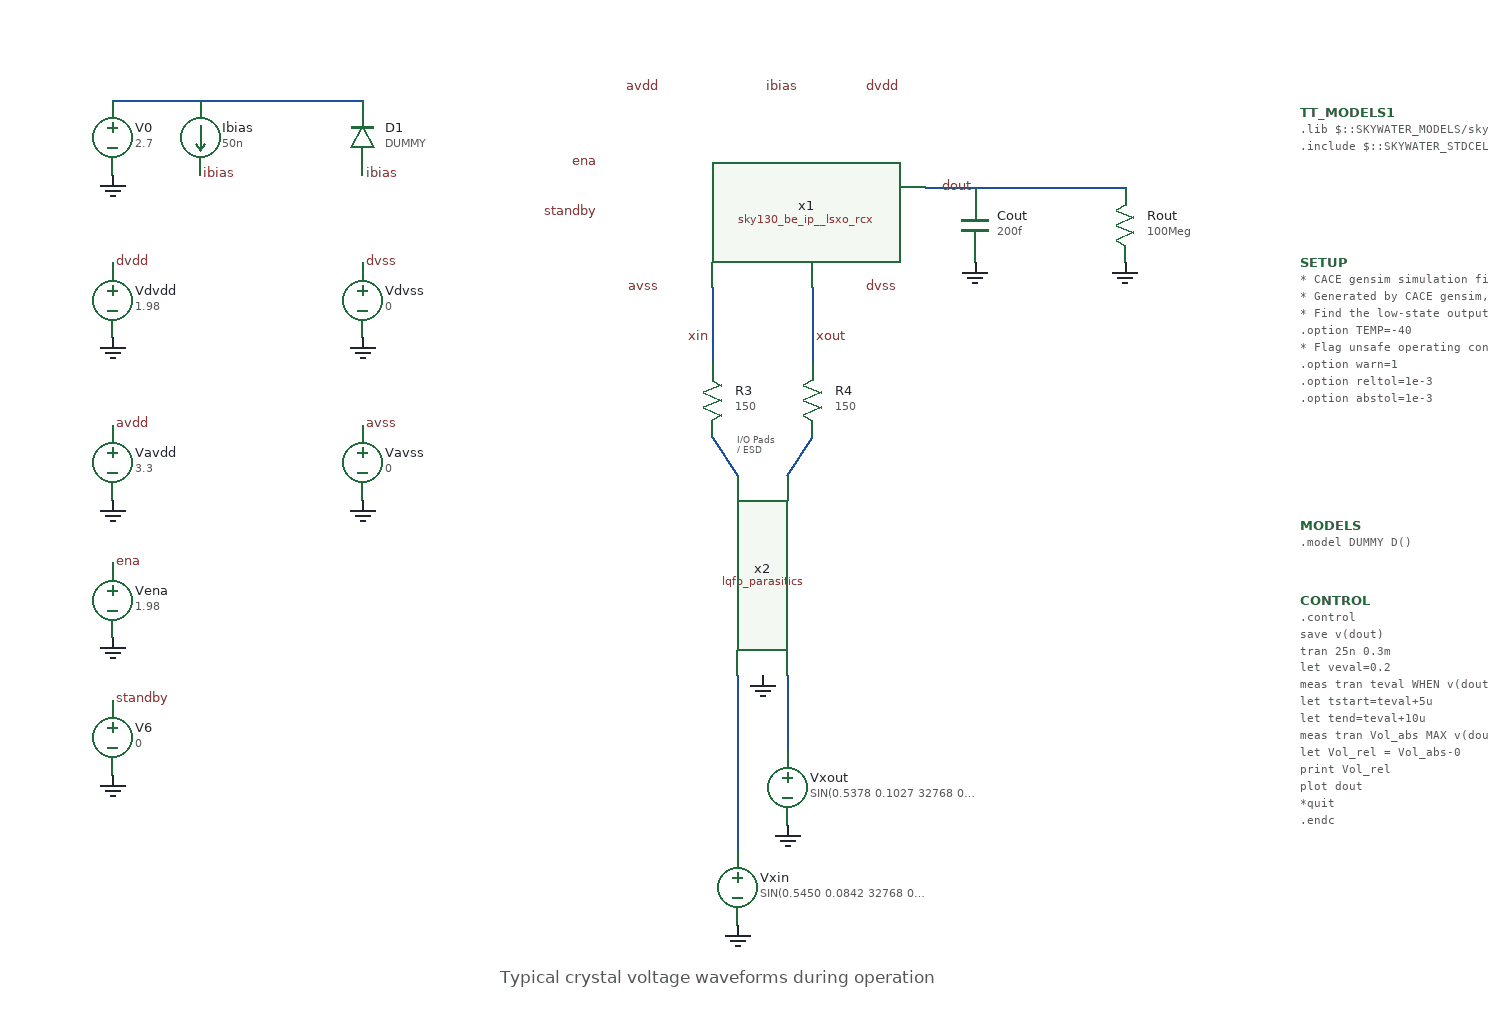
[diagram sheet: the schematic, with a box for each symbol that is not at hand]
v {xschem version=3.4.5 file_version=1.2
}
G {}
K {}
V {}
S {}
E {}
T {I/O Pads 
/ ESD} 540 -460 0 0 0.2 0.2 {}
T {Typical crystal voltage waveforms during operation} 350 -30 0 0 0.4 0.4 {}
N 40 -720 110 -720 {
lab=#net1}
N 600 -570 600 -510 {
lab=xout}
N 520 -570 520 -510 {
lab=xin}
N 520 -450 540 -420 {
lab=#net2}
N 580 -420 600 -450 {
lab=#net3}
N 110 -720 240 -720 {
lab=#net1}
N 690 -650 730 -650 {
lab=dout}
N 730 -650 850 -650 {
lab=dout}
N 540 -260 540 -120 {
lab=#net4}
N 580 -260 580 -200 {
lab=#net5}
C {devices/vsource.sym} 40 -560 0 0 {name=Vdvdd value=1.98 savecurrent=false}
C {devices/vsource.sym} 40 -430 0 0 {name=Vavdd value=3.3 savecurrent=false}
C {devices/lab_pin.sym} 40 -460 2 0 {name=p1 sig_type=std_logic lab=avdd}
C {devices/lab_pin.sym} 40 -590 2 0 {name=p2 sig_type=std_logic lab=dvdd}
C {devices/lab_pin.sym} 430 -670 0 0 {name=p3 sig_type=std_logic lab=ena
}
C {devices/code_shown.sym} 990 -380 0 0 {name=MODELS 
only_toplevel=true
value=".model DUMMY D()"}
C {devices/isource.sym} 110 -690 0 0 {name=Ibias value=50n}
C {devices/capa.sym} 730 -620 0 0 {name=Cout
m=1
value=200f
footprint=1206
device="ceramic capacitor"}
C {devices/gnd.sym} 730 -590 0 0 {name=l9 lab=GND}
C {devices/lab_pin.sym} 730 -650 1 0 {name=p16 sig_type=std_logic lab=dout}
C {devices/lab_pin.sym} 110 -660 2 0 {name=p17 sig_type=std_logic lab=ibias}
C {devices/vsource.sym} 40 -690 0 0 {name=V0 value=2.7 savecurrent=false}
C {devices/gnd.sym} 40 -660 0 0 {name=l10 lab=GND}
C {devices/lab_pin.sym} 520 -530 0 0 {name=p15 sig_type=std_logic lab=xin}
C {devices/lab_pin.sym} 600 -530 2 0 {name=p18 sig_type=std_logic lab=xout}
C {devices/lab_pin.sym} 480 -730 0 0 {name=p20 sig_type=std_logic lab=avdd}
C {devices/lab_pin.sym} 640 -730 2 0 {name=p22 sig_type=std_logic lab=dvdd}
C {devices/gnd.sym} 40 -530 0 0 {name=l1 lab=GND}
C {devices/gnd.sym} 40 -400 0 0 {name=l2 lab=GND}
C {devices/lab_pin.sym} 560 -730 2 0 {name=p11 sig_type=std_logic lab=ibias}
C {devices/gnd.sym} 40 -290 0 0 {name=l11 lab=GND}
C {devices/lab_pin.sym} 40 -350 2 0 {name=p4 sig_type=std_logic lab=ena}
C {devices/vsource.sym} 40 -210 0 0 {name=V6 value=0 savecurrent=false}
C {devices/gnd.sym} 40 -180 0 0 {name=l12 lab=GND}
C {devices/lab_pin.sym} 40 -240 2 0 {name=p5 sig_type=std_logic lab=standby}
C {devices/res.sym} 520 -480 0 0 {name=R3
value=150
footprint=1206
device=resistor
m=1}
C {devices/res.sym} 600 -480 0 1 {name=R4
value=150
footprint=1206
device=resistor
m=1}
C {lqfp_parasitics.sym} 560 -340 3 1 {name=x2}
C {devices/gnd.sym} 560 -260 0 0 {name=l13 lab=GND}
C {devices/vsource.sym} 40 -320 0 0 {name=Vena value=1.98 savecurrent=false}
C {devices/lab_pin.sym} 430 -630 0 0 {name=p6 sig_type=std_logic lab=standby}
C {devices/lab_pin.sym} 240 -660 2 0 {name=p7 sig_type=std_logic lab=ibias}
C {devices/diode.sym} 240 -690 2 0 {name=D1 model=DUMMY area=100}
C {devices/vsource.sym} 240 -560 0 0 {name=Vdvss value=0 savecurrent=false}
C {devices/gnd.sym} 240 -530 0 0 {name=l3 lab=GND}
C {devices/vsource.sym} 240 -430 0 0 {name=Vavss value=0 savecurrent=false}
C {devices/gnd.sym} 240 -400 0 0 {name=l4 lab=GND}
C {devices/lab_pin.sym} 240 -460 2 0 {name=p8 sig_type=std_logic lab=avss}
C {devices/lab_pin.sym} 240 -590 2 0 {name=p9 sig_type=std_logic lab=dvss}
C {devices/lab_pin.sym} 640 -570 2 0 {name=p10 sig_type=std_logic lab=dvss}
C {devices/lab_pin.sym} 480 -570 0 0 {name=p12 sig_type=std_logic lab=avss}
C {devices/res.sym} 850 -620 0 1 {name=Rout
value=100Meg
footprint=1206
device=resistor
m=1}
C {devices/gnd.sym} 850 -590 0 0 {name=l5 lab=GND}
C {devices/code_shown.sym} 990 -320 0 0 {name=CONTROL only_toplevel=false value=".control
save v(dout)

tran 25n 0.3m

let veval=0.2
meas tran teval WHEN v(dout)=veval FALL=2
let tstart=teval+5u
let tend=teval+10u
meas tran Vol_abs MAX v(dout) from=tstart to=tend
let Vol_rel = Vol_abs-0
print Vol_rel

plot dout
*quit
.endc
"}
C {devices/code_shown.sym} 990 -590 0 0 {name=SETUP only_toplevel=false value="* CACE gensim simulation file \{filename\}_\{N\}
* Generated by CACE gensim, Efabless Corporation (c) 2023
* Find the low-state output voltage on 'dout'

.option TEMP=-40
* Flag unsafe operating conditions (exceeds models' specified limits)
.option warn=1
.option reltol=1e-3
.option abstol=1e-3
"}
C {devices/vsource.sym} 580 -170 0 0 {name=Vxout value="SIN(0.5378 0.1027 32768 0 0 130)" savecurrent=false}
C {devices/vsource.sym} 540 -90 0 0 {name=Vxin value="SIN(0.5450 0.0842 32768 0 0 0)" savecurrent=false}
C {devices/gnd.sym} 580 -140 0 0 {name=l6 lab=GND}
C {devices/gnd.sym} 540 -60 0 0 {name=l7 lab=GND}
C {devices/code_shown.sym} 990 -710 0 0 {name=TT_MODELS1
only_toplevel=true
format="tcleval(@value )"
value="
.lib $::SKYWATER_MODELS/sky130.lib.spice sf
.include $::SKYWATER_STDCELLS/sky130_fd_sc_hd.spice
"
spice_ignore=false
place=header}
C {sky130_be_ip__lsxo_rcx.sym} 560 -650 0 0 {name=x1}
